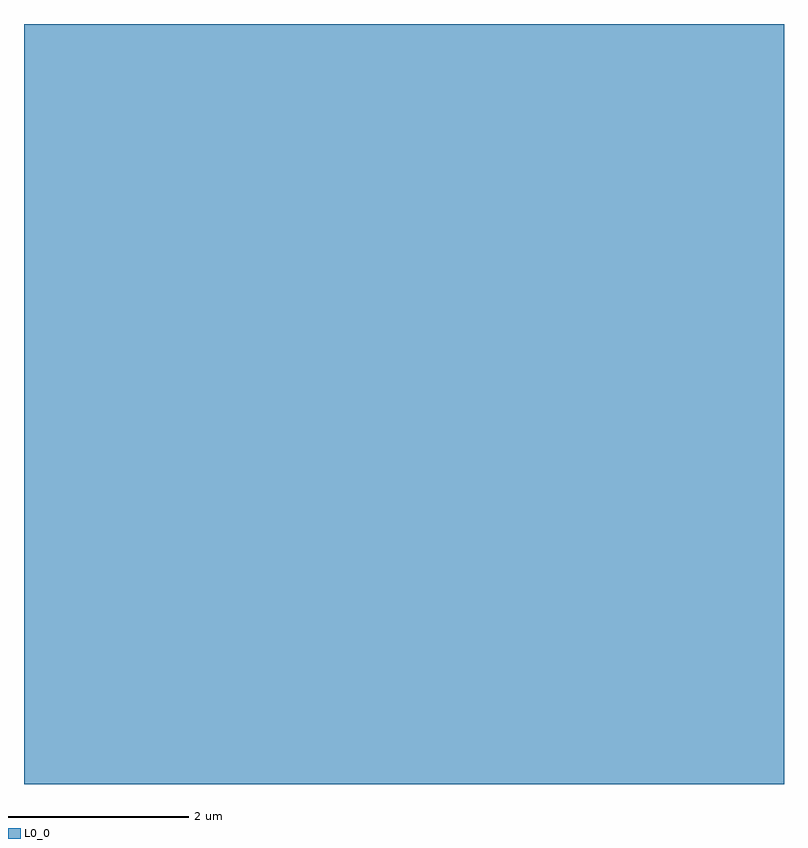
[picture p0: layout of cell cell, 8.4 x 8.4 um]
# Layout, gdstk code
import gdstk
lib = gdstk.Library(unit=1e-6, precision=1e-09)
def R(c, l, rs):  # rectangles x0, y0, x1, y1
    for r in rs: c.add(gdstk.rectangle(r[:2], r[2:], *l))
def A(c, l, x, y, w, h, nx, ny, dx, dy):  # array of equal rectangles
    R(c, l, [(x+i*dx, y+j*dy, x+i*dx+w, y+j*dy+h) for i in range(nx) for j in range(ny)])
L0_0 = (0, 0)

cell = lib.new_cell('cell')
A(cell, L0_0, -0.494, -3.694, 0.188, 0.188, 3, 2, 0.4, 7.2)
A(cell, L0_0, -0.893, -3.693, 0.186, 0.186, 1, 4, 0, 2.4)
A(cell, L0_0, 0.707, -3.693, 0.186, 0.186, 1, 4, 0, 2.4)
A(cell, L0_0, -0.913, -3.313, 0.226, 0.226, 5, 2, 0.4, 6.4)
A(cell, L0_0, -0.528, -2.928, 0.256, 0.256, 3, 2, 0.4, 5.6)
A(cell, L0_0, -0.55, -2.55, 0.3, 0.3, 3, 2, 0.4, 4.8)
A(cell, L0_0, -0.461, -2.061, 0.122, 0.122, 3, 2, 0.4, 4)
A(cell, L0_0, -0.495, -1.295, 0.19, 0.19, 3, 2, 0.4, 2.4)
A(cell, L0_0, -3.313, -0.913, 0.226, 0.226, 1, 5, 0, 0.4)
A(cell, L0_0, 3.087, -0.913, 0.226, 0.226, 1, 5, 0, 0.4)
A(cell, L0_0, -0.498, -0.898, 0.196, 0.196, 3, 2, 0.4, 1.6)
A(cell, L0_0, -3.693, -0.893, 0.186, 0.186, 4, 2, 2.4, 1.6)
A(cell, L0_0, -2.55, -0.55, 0.3, 0.3, 1, 3, 0, 0.4)
A(cell, L0_0, 2.25, -0.55, 0.3, 0.3, 1, 3, 0, 0.4)
A(cell, L0_0, -2.928, -0.528, 0.256, 0.256, 1, 3, 0, 0.4)
A(cell, L0_0, 2.672, -0.528, 0.256, 0.256, 1, 3, 0, 0.4)
A(cell, L0_0, -0.898, -0.498, 0.196, 0.196, 1, 3, 0, 0.4)
A(cell, L0_0, 0.702, -0.498, 0.196, 0.196, 1, 3, 0, 0.4)
A(cell, L0_0, -1.295, -0.495, 0.19, 0.19, 1, 3, 0, 0.4)
A(cell, L0_0, 1.105, -0.495, 0.19, 0.19, 1, 3, 0, 0.4)
A(cell, L0_0, -3.694, -0.494, 0.188, 0.188, 1, 3, 0, 0.4)
A(cell, L0_0, 3.506, -0.494, 0.188, 0.188, 1, 3, 0, 0.4)
A(cell, L0_0, -2.061, -0.461, 0.122, 0.122, 1, 3, 0, 0.4)
A(cell, L0_0, 1.939, -0.461, 0.122, 0.122, 1, 3, 0, 0.4)
A(cell, L0_0, -0.5, -0.1, 0.2, 0.2, 3, 1, 0.4, 0)
R(cell, L0_0, [(-4.2,-4.2,4.2,4.2), (-2.948,-4.148,-2.652,-3.852), (2.652,-4.148,2.948,-3.852), (-3.331,-4.131,-3.069,-3.869), (3.069,-4.131,3.331,-3.869), (-0.087,-4.087,0.087,-3.913), (-3.686,-4.086,-3.514,-3.914), (3.514,-4.086,3.686,-3.914), (-0.879,-4.079,-0.721,-3.921), (-0.479,-4.079,-0.321,-3.921), (0.321,-4.079,0.479,-3.921), (0.721,-4.079,0.879,-3.921), (-1.277,-4.077,-1.123,-3.923), (1.123,-4.077,1.277,-3.923), (-1.671,-4.071,-1.529,-3.929), (1.529,-4.071,1.671,-3.929), (-2.069,-4.069,-1.931,-3.931), (1.931,-4.069,2.069,-3.931), (-4.068,-4.068,-3.932,-3.932), (3.932,-4.068,4.068,-3.932), (-2.466,-4.066,-2.334,-3.934), (2.334,-4.066,2.466,-3.934), (-3.75,-3.75,-3.45,-3.45), (3.45,-3.75,3.75,-3.45), (-3.348,-3.748,-3.052,-3.452), (3.052,-3.748,3.348,-3.452), (-1.29,-3.69,-1.11,-3.51), (1.11,-3.69,1.29,-3.51), (-1.687,-3.687,-1.513,-3.513), (1.513,-3.687,1.687,-3.513), (-4.086,-3.686,-3.914,-3.514), (3.914,-3.686,4.086,-3.514), (-2.078,-3.678,-1.922,-3.522), (1.922,-3.678,2.078,-3.522), (-2.471,-3.671,-2.329,-3.529), (2.329,-3.671,2.471,-3.529), (-2.867,-3.667,-2.733,-3.533), (2.733,-3.667,2.867,-3.533), (-3.748,-3.348,-3.452,-3.052), (3.452,-3.348,3.748,-3.052), (-4.131,-3.331,-3.869,-3.069), (3.869,-3.331,4.131,-3.069), (-1.298,-3.298,-1.102,-3.102), (1.102,-3.298,1.298,-3.102), (-1.695,-3.295,-1.505,-3.105), (1.505,-3.295,1.695,-3.105), (-2.091,-3.291,-1.909,-3.109), (1.909,-3.291,2.091,-3.109), (-2.487,-3.287,-2.313,-3.113), (2.313,-3.287,2.487,-3.113), (-2.876,-3.276,-2.724,-3.124), (2.724,-3.276,2.876,-3.124), (-3.268,-3.268,-3.132,-3.132), (3.132,-3.268,3.268,-3.132), (-4.148,-2.948,-3.852,-2.652), (3.852,-2.948,4.148,-2.652), (-1.327,-2.927,-1.073,-2.673), (-0.927,-2.927,-0.673,-2.673), (0.673,-2.927,0.927,-2.673), (1.073,-2.927,1.327,-2.673), (-1.713,-2.913,-1.487,-2.687), (1.487,-2.913,1.713,-2.687), (-2.097,-2.897,-1.903,-2.703), (1.903,-2.897,2.097,-2.703), (-2.493,-2.893,-2.307,-2.707), (2.307,-2.893,2.493,-2.707), (-2.887,-2.887,-2.713,-2.713), (2.713,-2.887,2.887,-2.713), (-3.276,-2.876,-3.124,-2.724), (3.124,-2.876,3.276,-2.724), (-3.667,-2.867,-3.533,-2.733), (3.533,-2.867,3.667,-2.733), (-0.93,-2.53,-0.67,-2.27), (0.67,-2.53,0.93,-2.27), (-1.329,-2.529,-1.071,-2.271), (1.071,-2.529,1.329,-2.271), (-1.727,-2.527,-1.473,-2.273), (1.473,-2.527,1.727,-2.273), (-2.126,-2.526,-1.874,-2.274), (1.874,-2.526,2.126,-2.274), (-2.513,-2.513,-2.287,-2.287), (2.287,-2.513,2.513,-2.287), (-2.893,-2.493,-2.707,-2.307), (2.707,-2.493,2.893,-2.307), (-3.287,-2.487,-3.113,-2.313), (3.113,-2.487,3.287,-2.313), (-3.671,-2.471,-3.529,-2.329), (3.529,-2.471,3.671,-2.329), (-4.066,-2.466,-3.934,-2.334), (3.934,-2.466,4.066,-2.334), (-1.35,-2.15,-1.05,-1.85), (1.05,-2.15,1.35,-1.85), (-1.73,-2.13,-1.47,-1.87), (1.47,-2.13,1.73,-1.87), (-2.128,-2.128,-1.872,-1.872), (1.872,-2.128,2.128,-1.872), (-2.526,-2.126,-2.274,-1.874), (2.274,-2.126,2.526,-1.874), (-2.897,-2.097,-2.703,-1.903), (2.703,-2.097,2.897,-1.903), (-3.291,-2.091,-3.109,-1.909), (3.109,-2.091,3.291,-1.909), (-0.881,-2.081,-0.719,-1.919), (0.719,-2.081,0.881,-1.919), (-3.678,-2.078,-3.522,-1.922), (3.522,-2.078,3.678,-1.922), (-4.069,-2.069,-3.931,-1.931), (3.931,-2.069,4.069,-1.931), (-1.75,-1.75,-1.45,-1.45), (1.45,-1.75,1.75,-1.45), (-2.13,-1.73,-1.87,-1.47), (1.87,-1.73,2.13,-1.47), (-2.527,-1.727,-2.273,-1.473), (2.273,-1.727,2.527,-1.473), (-2.913,-1.713,-2.687,-1.487), (2.687,-1.713,2.913,-1.487), (-3.295,-1.695,-3.105,-1.505), (3.105,-1.695,3.295,-1.505), (-3.687,-1.687,-3.513,-1.513), (3.513,-1.687,3.687,-1.513), (-4.071,-1.671,-3.929,-1.529), (3.929,-1.671,4.071,-1.529), (-0.066,-1.666,0.066,-1.534), (-0.465,-1.665,-0.335,-1.535), (0.335,-1.665,0.465,-1.535), (-0.864,-1.664,-0.736,-1.536), (0.736,-1.664,0.864,-1.536), (-1.261,-1.661,-1.139,-1.539), (1.139,-1.661,1.261,-1.539), (-2.15,-1.35,-1.85,-1.05), (1.85,-1.35,2.15,-1.05), (-2.529,-1.329,-2.271,-1.071), (2.271,-1.329,2.529,-1.071), (-2.927,-1.327,-2.673,-1.073), (2.673,-1.327,2.927,-1.073), (-3.298,-1.298,-3.102,-1.102), (3.102,-1.298,3.298,-1.102), (-3.69,-1.29,-3.51,-1.11), (3.51,-1.29,3.69,-1.11), (-4.077,-1.277,-3.923,-1.123), (3.923,-1.277,4.077,-1.123), (-1.265,-1.265,-1.135,-1.135), (1.135,-1.265,1.265,-1.135), (-1.661,-1.261,-1.539,-1.139), (1.539,-1.261,1.661,-1.139), (-2.53,-0.93,-2.27,-0.67), (2.27,-0.93,2.53,-0.67), (-2.927,-0.927,-2.673,-0.673), (2.673,-0.927,2.927,-0.673), (-0.896,-0.896,-0.704,-0.704), (0.704,-0.896,0.896,-0.704), (-2.081,-0.881,-1.919,-0.719), (1.919,-0.881,2.081,-0.719), (-4.079,-0.879,-3.921,-0.721), (3.921,-0.879,4.079,-0.721), (-1.664,-0.864,-1.536,-0.736), (1.536,-0.864,1.664,-0.736), (-0.1,-0.5,0.1,-0.3), (-0.499,-0.499,-0.301,-0.301), (0.301,-0.499,0.499,-0.301), (-4.079,-0.479,-3.921,-0.321), (3.921,-0.479,4.079,-0.321), (-1.665,-0.465,-1.535,-0.335), (1.535,-0.465,1.665,-0.335), (-4.087,-0.087,-3.913,0.087), (3.913,-0.087,4.087,0.087), (-1.666,-0.066,-1.534,0.066), (1.534,-0.066,1.666,0.066), (-0.1,0.3,0.1,0.5), (-0.499,0.301,-0.301,0.499), (0.301,0.301,0.499,0.499), (-4.079,0.321,-3.921,0.479), (3.921,0.321,4.079,0.479), (-1.665,0.335,-1.535,0.465), (1.535,0.335,1.665,0.465), (-2.53,0.67,-2.27,0.93), (2.27,0.67,2.53,0.93), (-2.927,0.673,-2.673,0.927), (2.673,0.673,2.927,0.927), (-0.896,0.704,-0.704,0.896), (0.704,0.704,0.896,0.896), (-2.081,0.719,-1.919,0.881), (1.919,0.719,2.081,0.881), (-4.079,0.721,-3.921,0.879), (3.921,0.721,4.079,0.879), (-1.664,0.736,-1.536,0.864), (1.536,0.736,1.664,0.864), (-2.15,1.05,-1.85,1.35), (1.85,1.05,2.15,1.35), (-2.529,1.071,-2.271,1.329), (2.271,1.071,2.529,1.329), (-2.927,1.073,-2.673,1.327), (2.673,1.073,2.927,1.327), (-3.298,1.102,-3.102,1.298), (3.102,1.102,3.298,1.298), (-3.69,1.11,-3.51,1.29), (3.51,1.11,3.69,1.29), (-4.077,1.123,-3.923,1.277), (3.923,1.123,4.077,1.277), (-1.265,1.135,-1.135,1.265), (1.135,1.135,1.265,1.265), (-1.661,1.139,-1.539,1.261), (1.539,1.139,1.661,1.261), (-1.75,1.45,-1.45,1.75), (1.45,1.45,1.75,1.75), (-2.13,1.47,-1.87,1.73), (1.87,1.47,2.13,1.73), (-2.527,1.473,-2.273,1.727), (2.273,1.473,2.527,1.727), (-2.913,1.487,-2.687,1.713), (2.687,1.487,2.913,1.713), (-3.295,1.505,-3.105,1.695), (3.105,1.505,3.295,1.695), (-3.687,1.513,-3.513,1.687), (3.513,1.513,3.687,1.687), (-4.071,1.529,-3.929,1.671), (3.929,1.529,4.071,1.671), (-0.066,1.534,0.066,1.666), (-0.465,1.535,-0.335,1.665), (0.335,1.535,0.465,1.665), (-0.864,1.536,-0.736,1.664), (0.736,1.536,0.864,1.664), (-1.261,1.539,-1.139,1.661), (1.139,1.539,1.261,1.661), (-1.35,1.85,-1.05,2.15), (1.05,1.85,1.35,2.15), (-1.73,1.87,-1.47,2.13), (1.47,1.87,1.73,2.13), (-2.128,1.872,-1.872,2.128), (1.872,1.872,2.128,2.128), (-2.526,1.874,-2.274,2.126), (2.274,1.874,2.526,2.126), (-2.897,1.903,-2.703,2.097), (2.703,1.903,2.897,2.097), (-3.291,1.909,-3.109,2.091), (3.109,1.909,3.291,2.091), (-0.881,1.919,-0.719,2.081), (0.719,1.919,0.881,2.081), (-3.678,1.922,-3.522,2.078), (3.522,1.922,3.678,2.078), (-4.069,1.931,-3.931,2.069), (3.931,1.931,4.069,2.069), (-0.93,2.27,-0.67,2.53), (0.67,2.27,0.93,2.53), (-1.329,2.271,-1.071,2.529), (1.071,2.271,1.329,2.529), (-1.727,2.273,-1.473,2.527), (1.473,2.273,1.727,2.527), (-2.126,2.274,-1.874,2.526), (1.874,2.274,2.126,2.526), (-2.513,2.287,-2.287,2.513), (2.287,2.287,2.513,2.513), (-2.893,2.307,-2.707,2.493), (2.707,2.307,2.893,2.493), (-3.287,2.313,-3.113,2.487), (3.113,2.313,3.287,2.487), (-3.671,2.329,-3.529,2.471), (3.529,2.329,3.671,2.471), (-4.066,2.334,-3.934,2.466), (3.934,2.334,4.066,2.466), (-4.148,2.652,-3.852,2.948), (3.852,2.652,4.148,2.948), (-1.327,2.673,-1.073,2.927), (-0.927,2.673,-0.673,2.927), (0.673,2.673,0.927,2.927), (1.073,2.673,1.327,2.927), (-1.713,2.687,-1.487,2.913), (1.487,2.687,1.713,2.913), (-2.097,2.703,-1.903,2.897), (1.903,2.703,2.097,2.897), (-2.493,2.707,-2.307,2.893), (2.307,2.707,2.493,2.893), (-2.887,2.713,-2.713,2.887), (2.713,2.713,2.887,2.887), (-3.276,2.724,-3.124,2.876), (3.124,2.724,3.276,2.876), (-3.667,2.733,-3.533,2.867), (3.533,2.733,3.667,2.867), (-3.748,3.052,-3.452,3.348), (3.452,3.052,3.748,3.348), (-4.131,3.069,-3.869,3.331), (3.869,3.069,4.131,3.331), (-1.298,3.102,-1.102,3.298), (1.102,3.102,1.298,3.298), (-1.695,3.105,-1.505,3.295), (1.505,3.105,1.695,3.295), (-2.091,3.109,-1.909,3.291), (1.909,3.109,2.091,3.291), (-2.487,3.113,-2.313,3.287), (2.313,3.113,2.487,3.287), (-2.876,3.124,-2.724,3.276), (2.724,3.124,2.876,3.276), (-3.268,3.132,-3.132,3.268), (3.132,3.132,3.268,3.268), (-3.75,3.45,-3.45,3.75), (3.45,3.45,3.75,3.75), (-3.348,3.452,-3.052,3.748), (3.052,3.452,3.348,3.748), (-1.29,3.51,-1.11,3.69), (1.11,3.51,1.29,3.69), (-1.687,3.513,-1.513,3.687), (1.513,3.513,1.687,3.687), (-4.086,3.514,-3.914,3.686), (3.914,3.514,4.086,3.686), (-2.078,3.522,-1.922,3.678), (1.922,3.522,2.078,3.678), (-2.471,3.529,-2.329,3.671), (2.329,3.529,2.471,3.671), (-2.867,3.533,-2.733,3.667), (2.733,3.533,2.867,3.667), (-2.948,3.852,-2.652,4.148), (2.652,3.852,2.948,4.148), (-3.331,3.869,-3.069,4.131), (3.069,3.869,3.331,4.131), (-0.087,3.913,0.087,4.087), (-3.686,3.914,-3.514,4.086), (3.514,3.914,3.686,4.086), (-0.879,3.921,-0.721,4.079), (-0.479,3.921,-0.321,4.079), (0.321,3.921,0.479,4.079), (0.721,3.921,0.879,4.079), (-1.277,3.923,-1.123,4.077), (1.123,3.923,1.277,4.077), (-1.671,3.929,-1.529,4.071), (1.529,3.929,1.671,4.071), (-2.069,3.931,-1.931,4.069), (1.931,3.931,2.069,4.069), (-4.068,3.932,-3.932,4.068), (3.932,3.932,4.068,4.068), (-2.466,3.934,-2.334,4.066), (2.334,3.934,2.466,4.066)])

lib.write_gds('cell.gds')
